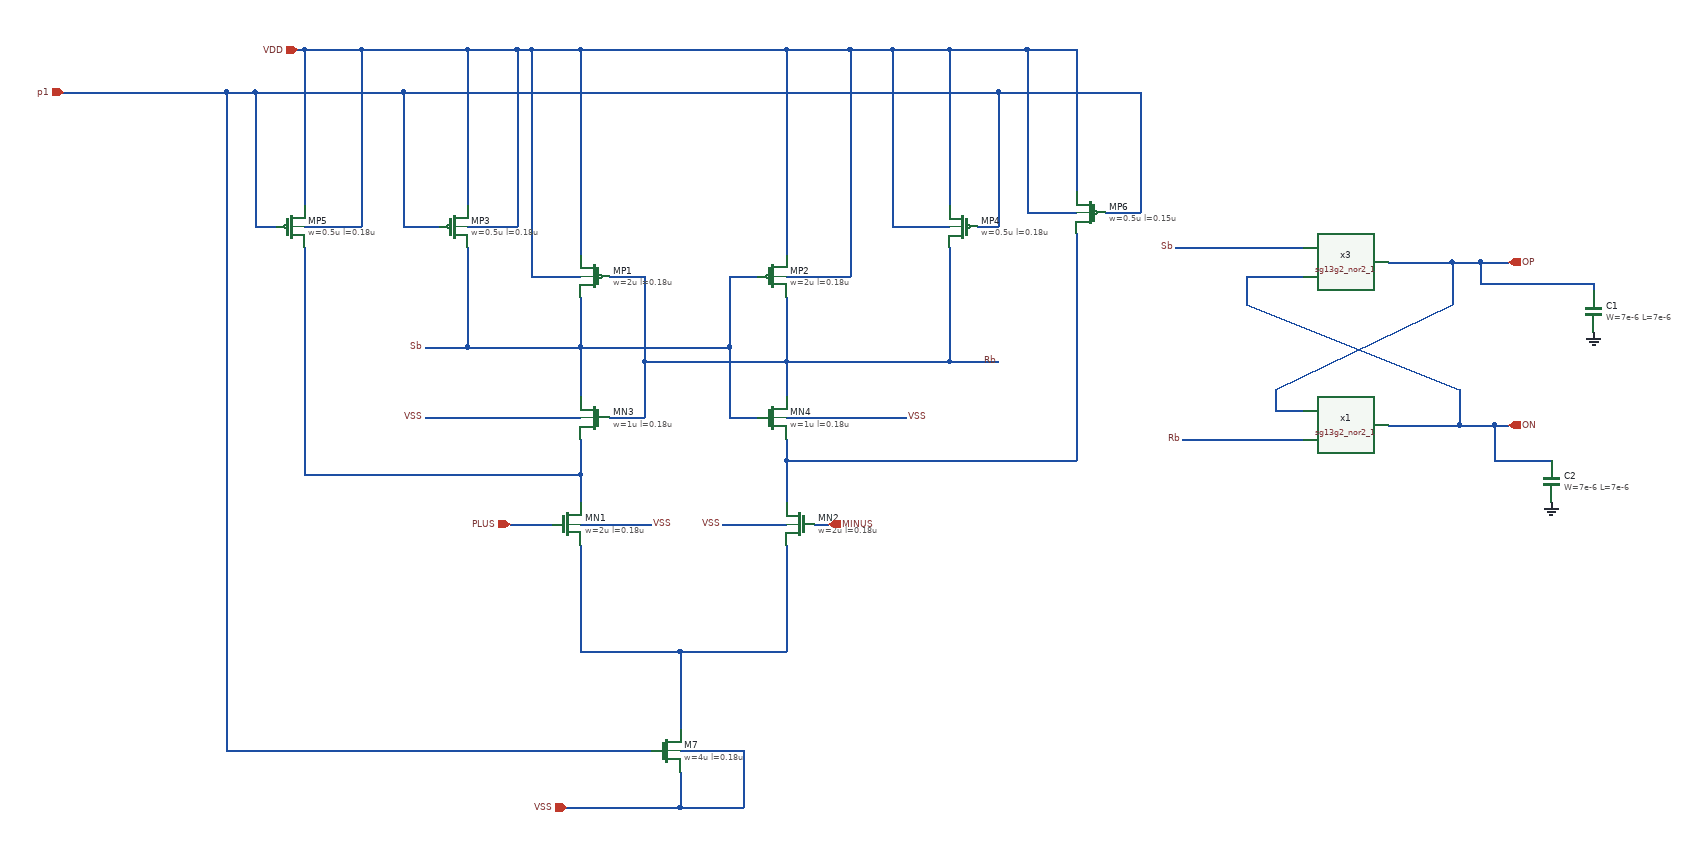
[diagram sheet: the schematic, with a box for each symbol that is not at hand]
v {xschem version=3.4.6 file_version=1.2}
G {}
K {}
V {}
S {}
E {}
N -400 -380 -400 -310 {lab=Sb}
N -110 -360 -110 -310 {lab=Rb}
N -400 -100 -400 50 {lab=#net1}
N -260 50 -110 50 {lab=#net1}
N -110 -100 -110 50 {lab=#net1}
N -360 -480 -310 -480 {lab=Rb}
N -310 -360 -310 -280 {lab=Rb}
N -360 -280 -310 -280 {lab=Rb}
N -190 -480 -150 -480 {lab=Sb}
N -190 -380 -190 -280 {lab=Sb}
N -190 -280 -150 -280 {lab=Sb}
N -560 -520 -560 -380 {lab=Sb}
N -560 -380 -400 -380 {lab=Sb}
N -400 -450 -400 -380 {lab=Sb}
N -400 -380 -190 -380 {lab=Sb}
N -190 -480 -190 -380 {lab=Sb}
N 120 -520 120 -360 {lab=Rb}
N -110 -360 120 -360 {lab=Rb}
N -110 -450 -110 -360 {lab=Rb}
N -310 -360 -110 -360 {lab=Rb}
N -310 -480 -310 -360 {lab=Rb}
N -260 50 -260 160 {lab=#net1}
N -400 50 -260 50 {lab=#net1}
N -500 -130 -440 -130 {lab=PLUS}
N -70 -130 -50 -130 {lab=MINUS}
N -650 -550 -600 -550 {lab=p1}
N -260 220 -260 270 {lab=VSS}
N -620 -380 -560 -380 {lab=Sb}
N 120 -360 190 -360 {lab=Rb}
N 870 -500 910 -500 {lab=OP}
N 890 -270 910 -270 {lab=ON}
N 440 -520 620 -520 {lab=Sb}
N 450 -250 620 -250 {lab=Rb}
N 540 -480 620 -480 {lab=ON}
N 540 -480 540 -440 {lab=ON}
N 540 -440 840 -320 {lab=ON}
N 840 -320 840 -270 {lab=ON}
N 740 -270 840 -270 {lab=ON}
N 580 -290 620 -290 {lab=OP}
N 580 -320 580 -290 {lab=OP}
N 580 -320 830 -440 {lab=OP}
N 830 -500 830 -440 {lab=OP}
N 740 -500 830 -500 {lab=OP}
N -260 190 -170 190 {lab=VSS}
N -170 190 -170 270 {lab=VSS}
N -260 270 -170 270 {lab=VSS}
N -400 -130 -300 -130 {lab=VSS}
N -420 270 -260 270 {lab=VSS}
N -110 -280 60 -280 {lab=#net2}
N -620 -280 -400 -280 {lab=#net3}
N -470 -480 -400 -480 {lab=VDD}
N -110 -480 -20 -480 {lab=VDD}
N -560 -550 -490 -550 {lab=VDD}
N -790 -550 -710 -550 {lab=VDD}
N 40 -550 120 -550 {lab=VDD}
N 230 -570 300 -570 {lab=VDD}
N 190 -740 390 -740 {lab=p1}
N -110 -220 -110 -160 {lab=#net4}
N 340 -570 390 -570 {lab=p1}
N 390 -740 390 -570 {lab=p1}
N -860 -550 -830 -550 {lab=p1}
N -860 -740 -860 -550 {lab=p1}
N -400 -200 -400 -160 {lab=#net5}
N -790 -800 -790 -580 {lab=VDD}
N -800 -800 -790 -800 {lab=VDD}
N -710 -800 -710 -550 {lab=VDD}
N -790 -800 -710 -800 {lab=VDD}
N -650 -740 -650 -550 {lab=p1}
N -860 -740 -650 -740 {lab=p1}
N -560 -800 -560 -580 {lab=VDD}
N -710 -800 -560 -800 {lab=VDD}
N -490 -800 -490 -550 {lab=VDD}
N -560 -800 -490 -800 {lab=VDD}
N -470 -800 -470 -480 {lab=VDD}
N -490 -800 -470 -800 {lab=VDD}
N -400 -800 -400 -510 {lab=VDD}
N -470 -800 -400 -800 {lab=VDD}
N -110 -800 -110 -510 {lab=VDD}
N -400 -800 -110 -800 {lab=VDD}
N -20 -800 -20 -480 {lab=VDD}
N -110 -800 -20 -800 {lab=VDD}
N 40 -800 40 -550 {lab=VDD}
N -20 -800 40 -800 {lab=VDD}
N 120 -800 120 -580 {lab=VDD}
N 40 -800 120 -800 {lab=VDD}
N 230 -800 230 -570 {lab=VDD}
N 120 -800 230 -800 {lab=VDD}
N 300 -800 300 -600 {lab=VDD}
N 230 -800 300 -800 {lab=VDD}
N 160 -550 190 -550 {lab=p1}
N 190 -740 190 -550 {lab=p1}
N -650 -740 190 -740 {lab=p1}
N -790 -520 -790 -200 {lab=#net5}
N -790 -200 -400 -200 {lab=#net5}
N -400 -250 -400 -200 {lab=#net5}
N 300 -540 300 -220 {lab=#net4}
N -110 -220 300 -220 {lab=#net4}
N -110 -250 -110 -220 {lab=#net4}
N -900 -740 -860 -740 {lab=p1}
N -900 190 -300 190 {lab=p1}
N -900 -740 -900 190 {lab=p1}
N -1130 -740 -900 -740 {lab=p1}
N 870 -500 870 -470 {lab=OP}
N 830 -500 870 -500 {lab=OP}
N 870 -470 1030 -470 {lab=OP}
N 1030 -470 1030 -460 {lab=OP}
N 890 -270 890 -220 {lab=ON}
N 840 -270 890 -270 {lab=ON}
N 890 -220 970 -220 {lab=ON}
N -200 -130 -110 -130 {lab=VSS}
C {sg13g2_pr/sg13_lv_nmos.sym} -380 -280 0 1 {name=MN3
l=0.18u
w=1u
ng=1
m=1
model=sg13_lv_nmos
spiceprefix=X
}
C {sg13g2_pr/sg13_lv_pmos.sym} -810 -550 0 0 {name=MP5
l=0.18u
w=0.5u
ng=1
m=1
model=sg13_lv_pmos
spiceprefix=X
}
C {sg13g2_pr/sg13_lv_pmos.sym} -580 -550 0 0 {name=MP3
l=0.18u
w=0.5u
ng=1
m=1
model=sg13_lv_pmos
spiceprefix=X
}
C {sg13g2_pr/sg13_lv_pmos.sym} -380 -480 0 1 {name=MP1
l=0.18u
w=2u
ng=1
m=1
model=sg13_lv_pmos
spiceprefix=X
}
C {sg13g2_pr/sg13_lv_pmos.sym} -130 -480 0 0 {name=MP2
l=0.18u
w=2u
ng=1
m=1
model=sg13_lv_pmos
spiceprefix=X
}
C {sg13g2_pr/sg13_lv_pmos.sym} 140 -550 0 1 {name=MP4
l=0.18u
w=0.5u
ng=1
m=1
model=sg13_lv_pmos
spiceprefix=X
}
C {sg13g2_pr/sg13_lv_pmos.sym} 320 -570 0 1 {name=MP6
l=0.15u
w=0.5u
ng=1
m=1
model=sg13_lv_pmos
spiceprefix=X
}
C {sg13g2_pr/sg13_lv_nmos.sym} -130 -280 0 0 {name=MN4
l=0.18u
w=1u
ng=1
m=1
model=sg13_lv_nmos
spiceprefix=X
}
C {sg13g2_pr/sg13_lv_nmos.sym} -420 -130 0 0 {name=MN1
l=0.18u
w=2u
ng=1
m=1
model=sg13_lv_nmos
spiceprefix=X
}
C {sg13g2_pr/sg13_lv_nmos.sym} -90 -130 0 1 {name=MN2
l=0.18u
w=2u
ng=1
m=1
model=sg13_lv_nmos
spiceprefix=X
}
C {sg13g2_pr/sg13_lv_nmos.sym} -280 190 0 0 {name=M7
l=0.18u
w=4u
ng=1
m=1
model=sg13_lv_nmos
spiceprefix=X
}
C {ipin.sym} -500 -130 0 0 {name=p1 lab=PLUS}
C {ipin.sym} -50 -130 0 1 {name=p2 lab=MINUS}
C {ipin.sym} -800 -800 0 0 {name=p5 lab=VDD}
C {ipin.sym} -420 270 0 0 {name=p7 lab=VSS}
C {devices/title.sym} -630 370 0 0 {name=l5 author="Sneha Shree"}
C {opin.sym} 910 -500 0 0 {name=p3 lab=OP}
C {opin.sym} 910 -270 0 0 {name=p4 lab=ON}
C {devices/lab_wire.sym} -620 -380 0 0 {name=p8 sig_type=std_logic lab=Sb}
C {devices/lab_wire.sym} 190 -360 0 0 {name=p9 sig_type=std_logic lab=Rb}
C {devices/lab_wire.sym} 450 -250 0 0 {name=p10 sig_type=std_logic lab=Rb}
C {devices/lab_wire.sym} 440 -520 0 0 {name=p11 sig_type=std_logic lab=Sb}
C {sg13g2_stdcells/sg13g2_nor2_1.sym} 682.6995849609375 -499.6832275390625 0 0 {name=x3 VDD=VDD VSS=VSS prefix=sg13g2_ }
C {sg13g2_stdcells/sg13g2_nor2_1.sym} 681.4508056640625 -269.9664306640625 0 0 {name=x1 VDD=VDD VSS=VSS prefix=sg13g2_ }
C {ipin.sym} -1130 -740 0 0 {name=p12 lab=p1}
C {sg13g2_pr/cap_cmim.sym} 1030 -430 0 0 {name=C1 model=cap_cmim W=7e-6 L=7e-6 MF=1 spiceprefix=X}
C {sg13g2_pr/cap_cmim.sym} 970 -190 0 0 {name=C2 model=cap_cmim W=7e-6 L=7e-6 MF=1 spiceprefix=X}
C {devices/gnd.sym} 1030 -400 0 0 {name=l12 lab=GND}
C {devices/gnd.sym} 970 -160 0 0 {name=l1 lab=GND}
C {devices/lab_wire.sym} -200 -130 0 0 {name=p6 sig_type=std_logic lab=VSS}
C {devices/lab_wire.sym} -300 -130 0 1 {name=p13 sig_type=std_logic lab=VSS}
C {devices/lab_wire.sym} 60 -280 0 1 {name=p14 sig_type=std_logic lab=VSS}
C {devices/lab_wire.sym} -620 -280 0 0 {name=p15 sig_type=std_logic lab=VSS}
